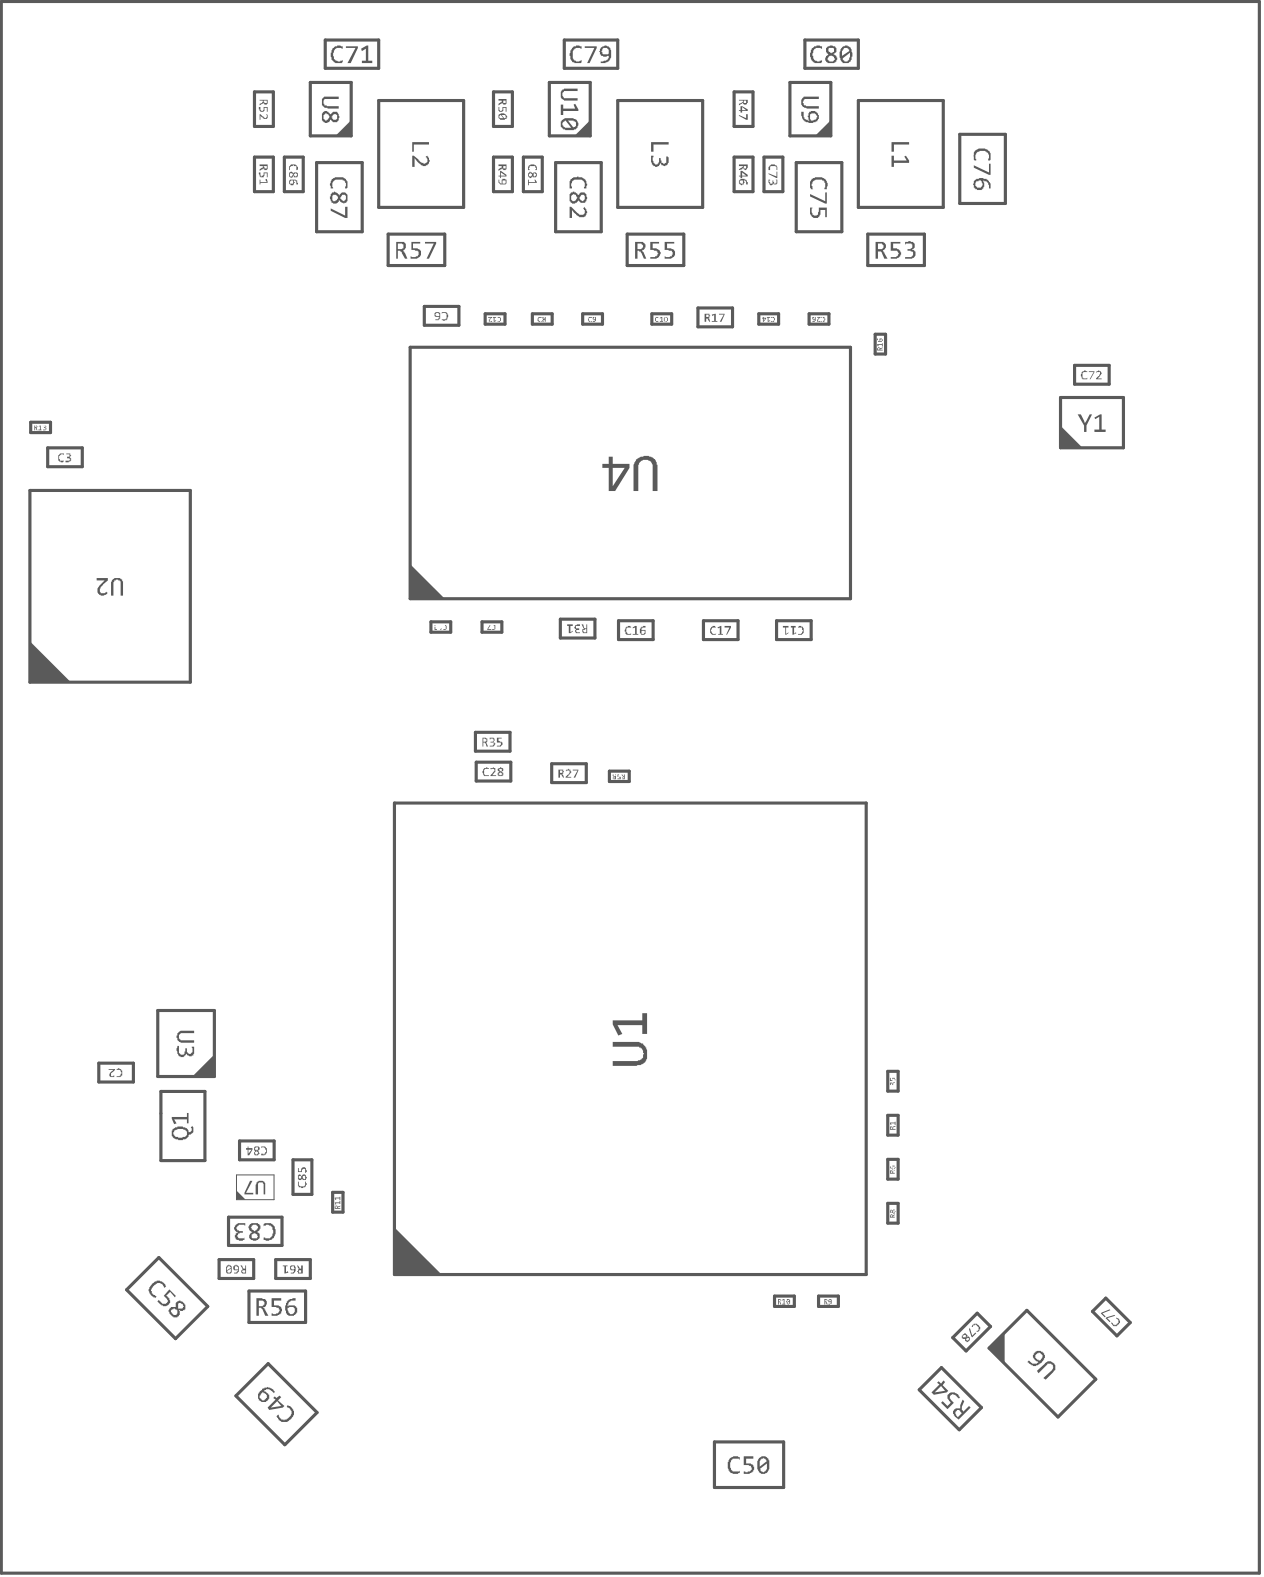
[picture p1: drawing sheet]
<svg xmlns="http://www.w3.org/2000/svg" width="134mm" height="167mm" viewBox="0 0 134 167" stroke-linecap="round" stroke-linejoin="round" font-family="sans-serif">
<path d="M.1 .2h133.1v166.3h-133.1z" fill="none" stroke="#5a5a5a" stroke-width=".33"/>
<g fill="#5a5a5a">
<path d="M25 126l1 .9h-1z"/>
<path d="M86.2 14.4l1.7-1.7v1.7z"/>
<path d="M60.8 14.4l1.6-1.7v1.7z"/>
<path d="M35.5 14.4l1.6-1.7v1.7z"/>
<path d="M43.4 59.7l3.6 3.7h-3.6z"/>
<path d="M41.7 129.9l5 5h-5z"/>
<path d="M104.6 142.6l1.7-1.6v3.3z"/>
<path d="M22.7 111.6v2.3h-2.4z"/>
<path d="M3.2 67.9l4.3 4.3h-4.3z"/>
<path d="M112.2 45.1l2.3 2.3h-2.3z"/>
</g>
<path d="M25 124.3h4v2.6h-4z" fill="none" stroke="#5a5a5a" stroke-width=".11"/>
<g fill="none" stroke="#5a5a5a" stroke-width=".33">
<path d="M26.9 9.7h2v3.7h-2zM26.9 16.6h2v3.7h-2zM30.1 16.6h2v3.7h-2zM32.8 8.7h4.3v5.7h-4.3zM33.5 17.2h4.8v7.3h-4.8zM34.4 4.2h5.7v3h-5.7zM40.1 10.6h8.9v11.3h-8.9zM52.2 9.7h2v3.7h-2zM52.2 16.6h2v3.7h-2zM55.4 16.6h2v3.7h-2zM58.1 8.7h4.3v5.7h-4.3zM58.8 17.2h4.8v7.3h-4.8z"/>
<path d="M59.7 4.2h5.6v3h-5.6zM65.3 10.6h9v11.3h-9zM77.7 9.7h1.9v3.7h-1.9zM77.7 16.6h1.9v3.7h-1.9zM80.8 16.6h2v3.7h-2zM83.6 8.7h4.3v5.7h-4.3zM84.2 17.2h4.8v7.3h-4.8zM85.1 4.2h5.7v3h-5.7zM90.8 10.6h9v11.3h-9zM101.5 14.2h4.8v7.3h-4.8zM41.1 24.8h5.9v3.3h-5.9zM43.4 36.7h46.6v26.7h-46.6z"/>
<path d="M44.9 32.4h3.6v2h-3.6zM51.3 33.2h2.1v1.1h-2.1zM56.3 33.2h2.1v1.1h-2.1zM61.6 33.2h2.1v1.1h-2.1zM66.3 24.8h6v3.3h-6zM69 33.2h2v1.1h-2zM73.8 32.6h3.7v2h-3.7zM80.3 33.2h2.1v1.1h-2.1zM85.6 33.2h2.1v1.1h-2.1zM91.8 24.8h6v3.3h-6zM92.6 35.4h1.1v2.1h-1.1zM113.7 38.7h3.6v2h-3.6z"/>
<path d="M3.2 51.9h16.9v20.3h-16.9zM3.2 44.7h2.1v1.1h-2.1zM5 47.4h3.7v2h-3.7zM112.2 42.1h6.6v5.3h-6.6zM45.6 65.8h2.1v1.1h-2.1zM50.3 77.5h3.6v2h-3.6zM51 65.8h2.1v1.1h-2.1zM59.3 65.5h3.6v2h-3.6zM65.4 65.7h3.7v2h-3.7zM74.4 65.7h3.7v2h-3.7zM82.1 65.7h3.7v2h-3.7zM41.7 85h49.9v49.9h-49.9z"/>
<path d="M50.4 80.6h3.6v2h-3.6zM58.4 80.8h3.6v2h-3.6zM64.5 81.6h2.1v1.1h-2.1zM10.5 112.5h3.6v2h-3.6zM16.7 106.9h6v7h-6zM17 115.5h4.7v7.3h-4.7zM93.9 113.4h1.1v2.1h-1.1zM93.9 118h1.1v2.1h-1.1zM13.4 136.5l3.4-3.4 5.2 5.1-3.4 3.4zM23.2 133.3h3.6v2h-3.6zM24.2 128.8h5.6v3h-5.6zM25.3 120.7h3.7v2h-3.7z"/>
<path d="M26.3 136.6h6v3.3h-6zM29.2 133.3h3.6v2h-3.6zM31 122.7h2v3.7h-2zM35.2 126.2h1.1v2.1h-1.1zM81.9 137.1h2.1v1.1h-2.1zM86.6 137.1h2.1v1.1h-2.1zM93.9 127.3h1.1v2.1h-1.1zM93.9 122.7h1.1v2.1h-1.1zM115.6 138.8l1.4-1.4 2.6 2.5-1.5 1.5zM25 147.7l3.4-3.4 5.1 5.2-3.4 3.4zM75.6 152.6h7.3v4.8h-7.3zM97.2 147.1l2.4-2.4 4.2 4.2-2.3 2.4z"/>
<path d="M100.8 141.5l2.6-2.6 1.4 1.5-2.6 2.5zM104.6 142.6l4-4 7.3 7.3-4 4z"/>
</g>
<g fill="#5a5a5a">
<path d="M27.1 125.1h.1a.48 .48 0 0 1 .7-.1l.2 .2v1.2h-.2v-1a.28 .28 0 0 0-.2-.3 .28 .28 0 0 0-.3 .1h-.1v1.2h-.3v-1z"/>
<path d="M26.4 124.9h.3l-.7 1.3h.8v.2h-.9v-.2z"/>
<path d="M43.5 25.6h.9v.2h-.7v.5h.5v.1a.32 .32 0 0 1 .3 .4v.1a.59 .59 0 0 1-.6 .5h-.5v-.3l.2 .1a.6 .6 0 0 0 .7-.2v-.4l-.1-.1-.7-.1z"/>
<path d="M45 25.6h1.1v.2l-.7 1.6h-.3l.8-1.6h-.9z"/>
<path d="M28.7 137.4h1v.2h-.7v.5h.5v.1l.2 .1a.63 .63 0 0 1-.5 .9h-.5v-.2h.1a.4 .4 0 0 0 .6-.1l.2-.2-.1-.3-.8-.1z"/>
<path d="M68.8 25.6h.9v.2h-.7v.5h.5v.1a.45 .45 0 0 1 .2 .7l-.2 .3h-.7v-.3v.1h.5l.3-.3-.1-.4-.7-.1z"/>
<path d="M70.3 25.6h1v.2h-.7v.5a.87 .87 0 0 1 .7 .1l.1 .2a.45 .45 0 0 1-.2 .6 .63 .63 0 0 1-.7 .2h-.2v-.3l.2 .1a.55 .55 0 0 0 .6-.2 .31 .31 0 0 0 0-.4 .31 .31 0 0 0-.4-.1v-.1h-.4z"/>
<path d="M100.2 147.6l.1-.1a.73 .73 0 0 1 1.1 .2l.2 .1-.2 .2-.3-.4h-.2a.3 .3 0 0 0-.3 0 .3 .3 0 0 0-.1 .3l.4 .5-.7 .7-.7-.7 .2-.1 .5 .5 .4-.4-.2-.2a.55 .55 0 0 1-.2-.6z"/>
<path d="M94.2 25.6h1v.2h-.7v.5h.4v.1a.3 .3 0 0 1 .3 .3h.1v.3h-.1a.3 .3 0 0 1-.3 .3v.1h-.7v-.2h.2a.46 .46 0 0 0 .6-.2 .26 .26 0 0 0 0-.4 .26 .26 0 0 0-.3-.1h-.5z"/>
<path d="M95.7 25.6h.4v-.1h.2l.1 .1a.32 .32 0 0 1 .4 .4v.2l-.3 .2a.32 .32 0 0 1 .3 .5 .32 .32 0 0 1-.3 .4v.1h-.8v-.2h.3a.38 .38 0 0 0 .5-.2 .24 .24 0 0 0 .1-.2 .24 .24 0 0 0-.3-.2v-.1h-.3v-.1h.2a.35 .35 0 0 0 .3-.5l-.1-.1h-.6l-.1 .1z"/>
<path d="M68.9 15h1.8v.3h-1.6v.8h-.2z"/>
<path d="M68.9 16.5h.2v.1h-.1a.55 .55 0 0 0 .2 .6 .22 .22 0 0 0 .2 .2 .22 .22 0 0 0 .2-.2h.1v-.5h.2v.3h.1v.2h.1a.3 .3 0 0 0 .3 0 .3 .3 0 0 0 .1-.4v-.2a.34 .34 0 0 1 .2 .5l-.1 .3-.1 .1a.33 .33 0 0 1-.5-.1l-.1-.2-.1 .1a.45 .45 0 0 1-.5 .4v-.1a.3 .3 0 0 1-.3-.4h-.1z"/>
<path d="M43.6 15h1.8v.3h-1.6v.8h-.2z"/>
<path d="M43.6 16.5h.2l.6 .7h.4v.1a.34 .34 0 0 0 .4-.4l-.1-.3h-.1l.2-.1 .2 .2v.2a.38 .38 0 0 1-.2 .5l-.2 .2-.5-.1-.6-.8v1h-.3z"/>
<path d="M94.3 15h1.9v.3h-1.6v.8h-.3z"/>
<path d="M94.3 16.5h.3v.5h1.3l-.2-.4 .1-.1 .4 .5v.2h-1.6v.5h-.3z"/>
<path d="M35.1 19a1.45 1.45 0 0 1 1.2-.2 .73 .73 0 0 1 .4 1.1h-.3a.55 .55 0 0 0 .2-.6h-.1v-.1a1.27 1.27 0 0 0-1.3 0v.1v.6h-.2l-.1-.5z"/>
<path d="M35 22.1l1.5 .7v-.9h.3v1.2h-.3l-1.5-.8z"/>
<path d="M27.9 129.5a.98 .98 0 0 1 1.1 .2 1.15 1.15 0 0 1-.2 1.4l-.1 .1h-.2v.1l-.6-.1v-.3l.2 .1a.46 .46 0 0 0 .6-.2h.1v-.3h.1l-.1-.5a.3 .3 0 0 0-.3-.3l-.1-.1h-.3v.1l-.2 .1z"/>
<path d="M24.8 129.7l.2-.1a.63 .63 0 0 1 .7-.2h.2v.3a.57 .57 0 0 0-.9 .3l.3 .3h.4v.1h-.3l-.3 .3a.35 .35 0 0 0 .5 .3h.3v-.1v.3l-.6 .1v-.1h-.3l-.1-.1-.1-.4 .4-.3a.43 .43 0 0 1-.4-.6z"/>
<path d="M60.3 19l.4-.2h.1a1.26 1.26 0 0 1 1.1 .2l.2 .6-.1 .1v.2h-.2a.56 .56 0 0 0 0-.7 .56 .56 0 0 0-.6-.2 .6 .6 0 0 0-.8 .5l.1 .4h-.3v-.7z"/>
<path d="M60.2 21.9h.2l.8 .7a.36 .36 0 0 0 .6 0 .4 .4 0 0 0-.1-.5l.2-.2v.2a.33 .33 0 0 1 .1 .5 .47 .47 0 0 1-.7 .4l-.3-.2-.5-.6v.9h-.3z"/>
<path d="M85.9 5.2l.2-.3h.3v-.1l.6 .1v.3l-.3-.1a.46 .46 0 0 0-.6 .2h-.1v.3l-.1 .1v.2l.1 .1a.32 .32 0 0 0 .4 .4v.1h.3v-.1l.3-.1v.3a.8 .8 0 0 1-1.2-.4l-.1-.6h.1z"/>
<path d="M60.5 5.1l.2-.2h.2v-.1h.4l.2 .1v.3a.6 .6 0 0 0-.6-.1 .6 .6 0 0 0-.3 .6 .47 .47 0 0 0 .3 .7v.1h.4l.2-.2v.3a.84 .84 0 0 1-1.2-.3l-.1-.6z"/>
<path d="M61.9 4.9h1.2v.2l-.7 1.6h-.3l.8-1.6h-1z"/>
<path d="M103.1 16a1.38 1.38 0 0 1 1.3-.2v.1a.79 .79 0 0 1 .3 1.1h-.2v-.2a.45 .45 0 0 0-.1-.7 .63 .63 0 0 0-.7-.1l-.1 .1a.46 .46 0 0 0-.4 .5l.1 .4h-.2l-.2-.5h.1z"/>
<path d="M103 17.5l1.6 .7v-.9h.2v1.2h-.2l-1.6-.8z"/>
<path d="M85.9 18.9a1.48 1.48 0 0 1 1.5 .1l.1 .3v.7h-.3v-.1h.1a.63 .63 0 0 0-.6-.9h-.1a.53 .53 0 0 0-.7 .3v.1v.3v.2l.1 .1h-.2l-.1-.4a.55 .55 0 0 1 .2-.6z"/>
<path d="M85.7 20.5l1.6 .8v-.9h.2v1.1h-.2l-1.6-.7z"/>
<path d="M85.7 22h.2v.1a.6 .6 0 0 0 .2 .7l.4-.1 .1-.7h.9v1h-.2v-.8h-.5v.5h-.1a.32 .32 0 0 1-.4 .4h-.1a.59 .59 0 0 1-.5-.6z"/>
<path d="M35.2 5.2l.2-.3h.3v-.1l.6 .1v.3l-.3-.1a.46 .46 0 0 0-.6 .2h-.1v.3h-.1l.1 .5a.3 .3 0 0 0 .4 .3v.1h.3v-.1l.3-.1v.3a.98 .98 0 0 1-1.1-.2 1.12 1.12 0 0 1 0-1.2z"/>
<path d="M36.6 4.9h1.3v.2l-.8 1.6h-.3l.8-1.6h-1z"/>
<path d="M38.2 5.2l.6-.4h.2v1.6h.4v.3h-1.1v-.3h.4v-1.2l-.4 .2z"/>
<path d="M16.1 135.8l.4-.2a.86 .86 0 0 1 1.1 .5l-.2 .2-.2-.5h-.3a1.04 1.04 0 0 0-.9 .8l.1 .1a.3 .3 0 0 0 .3 .3l.2 .2-.2 .2v-.1a.76 .76 0 0 1-.6-.6 .76 .76 0 0 1 .3-.8z"/>
<path d="M16.6 137.7l.2-.2 .2 .2a.39 .39 0 0 0 .4 .3 .39 .39 0 0 0 .3-.5l-.4-.4 .6-.7 .7 .7-.1 .2-.5-.6-.4 .4 .3 .3a.45 .45 0 0 1-.2 .7l-.5 .1v-.1h-.1z"/>
<path d="M77.2 154.3l.4-.2h.5v.1h.1v.2v-.1h-.3a.38 .38 0 0 0-.5 .2 .63 .63 0 0 0-.2 .7l.1 .2a.32 .32 0 0 0 .4 .3h.5v-.1v.3h-.2a.84 .84 0 0 1-1-.6v-.6h.1z"/>
<path d="M78.7 154.1h1v.2h-.8v.6h.4a.51 .51 0 0 1 .4 .7l-.1 .2-.3 .1h-.6v-.2h.1v.1h.3l.1-.1a.32 .32 0 0 0 .3-.4h-.1v-.2l-.2-.1h-.5z"/>
<path d="M29.2 149.9l.3-.2 .1 .3 .1 .2a.88 .88 0 0 0 1.1-.6v-.3l-.1-.3-.4-.1 .1-.2 .1 .1a.79 .79 0 0 1 .5 1.1l-.2 .2a.81 .81 0 0 1-1.2 .2h-.1z"/>
<path d="M29.9 133.9h.5v.1h-.1v.7l.1-.2 .1 .2h-.4v-.7h-.2z"/>
<path d="M27.4 11.3h.1v.3a.18 .18 0 0 0 .3 .1 .18 .18 0 0 0 .1-.2v-.2h.4v.5h-.1v-.4h-.2v.3a.26 .26 0 0 1-.3 .1 .26 .26 0 0 1-.2-.2h-.1z"/>
<path d="M27.5 12.1l.4 .2a.18 .18 0 0 0 .2 .2 .18 .18 0 0 0 .1-.2l-.1-.1 .1-.1a.28 .28 0 0 1 .1 .3 .28 .28 0 0 1-.2 .2h-.2l-.4-.3v.4z"/>
<path d="M27.4 18.2h.1v.4l.1 .1 .3-.2v-.3h.4v.6h-.1v-.5h-.2v.2a.25 .25 0 0 1-.3 .3 .25 .25 0 0 1-.2-.3z"/>
<path d="M27.5 19v.3h.7l-.1-.3 .1-.1 .1 .4h-.8v.2z"/>
<path d="M52.7 11.3h.1v.3a.18 .18 0 0 0 .2 .1 .18 .18 0 0 0 .2-.2v-.2h.4v.5h-.1v-.4h-.3a.29 .29 0 0 1-.2 .4 .29 .29 0 0 1-.3-.4z"/>
<path d="M78.2 12.2l.7 .3v-.4h.2v.6h-.2l-.7-.4z"/>
<path d="M51.8 78.1a.34 .34 0 0 1 .5 .2l-.2 .2 .3 .2-.1 .1a.38 .38 0 0 1-.5 .2v-.1h.3l.1-.1v-.2h-.3v-.1h.2a.18 .18 0 0 0 .1-.2 .18 .18 0 0 0-.2-.2l-.2 .1z"/>
<path d="M52.6 78.1h.5h-.4v.3l.3 .1a.22 .22 0 0 1 .2 .2 .22 .22 0 0 1-.2 .2v.1h-.4v-.1h.3l.1-.1v-.2h-.4z"/>
<path d="M60.8 66.1h.5v.1h-.4v.3h.4v.2h-.3l-.1 .1 .1 .1h.3v.1a.34 .34 0 0 1-.5-.3l.2-.1-.2-.1z"/>
<path d="M60 66.1h.6v.1h-.3v.7l.3-.2-.3 .3h-.1v-.8h-.2z"/>
<path d="M59.8 81.5l.3-.1h.2l.1 .4-.4 .4h.4v.1h-.6l.4-.5v-.3h-.2l-.1 .1z"/>
<path d="M60.6 81.4h.6l-.4 .9h-.1l.4-.8h-.5z"/>
<path d="M75.3 33.3l.4-.1v.8h.2h-.6h.2v-.7l-.1 .2z"/>
<path d="M76.1 33.2h.5l-.3 .8h-.2l.5-.7h-.5z"/>
<path d="M30.6 17.6a.54 .54 0 0 1 .5-.2 .54 .54 0 0 1 .4 .4l-.1 .2v-.4h-.3v-.1l-.3 .1a.24 .24 0 0 0-.1 .2 .24 .24 0 0 0 .1 .2h-.2z"/>
<path d="M31.5 125h.2h-.1a.34 .34 0 0 0 0 .4 .34 .34 0 0 0 .3 .1h.2a.38 .38 0 0 0 .2-.5l.1 .2v.3h-.1a.33 .33 0 0 1-.5 .1 .34 .34 0 0 1-.3-.5z"/>
<path d="M31.5 123.6h.1v.3h.3a.28 .28 0 0 1 .1-.4 .28 .28 0 0 1 .4 .3v.3h-.1v-.4h-.3l-.1 .1v.2h-.4z"/>
<path d="M27.6 121.3a.38 .38 0 0 1 .5 .2l.1 .1a.55 .55 0 0 1-.1 .6h-.1h-.4v-.1l.3 .1 .2-.3v-.4l-.1-.1h-.3l-.1 .1z"/>
<path d="M55.9 17.5l.5-.1a.42 .42 0 0 1 .4 .4v.2h-.2l.1-.1-.1-.3h-.6v.1h-.1l.1 .3h-.1z"/>
<path d="M55.9 19v.3h.7l-.1-.3h.1l.2 .3h-.9v.3z"/>
<path d="M102.8 140.3l.2-.2a.52 .52 0 0 1 .6 .2 .52 .52 0 0 1 0 .5l-.1 .1-.2-.1a.31 .31 0 0 0 .2-.3 .31 .31 0 0 0-.2-.3h-.2h-.2v.2z"/>
<path d="M102.6 140.5l.2 .8 .4-.3 .1 .1-.5 .4-.3-.8z"/>
<path d="M117.5 140l.1-.1 .1 .3h.2h.2v-.1a.32 .32 0 0 0 .2-.4 .32 .32 0 0 0-.3-.2l.1-.1v.1h.2l.1 .1a.3 .3 0 0 1 .1 .4 .3 .3 0 0 1-.3 .2 .32 .32 0 0 1-.3 .1 .32 .32 0 0 1-.3-.2z"/>
<path d="M117 139.5l.9-.4 .1 .1-.9 .3 .4 .3-.1 .1z"/>
<path d="M116.4 139l1-.5 .1 .1-.9 .4 .4 .3-.1 .1z"/>
<path d="M81.3 17.7h.1a.44 .44 0 0 1 .5-.3 .44 .44 0 0 1 .3 .5v.1h-.1a.24 .24 0 0 0 0-.3 .24 .24 0 0 0-.2-.1h-.4v.1v.1h-.1h.1v.2h-.2z"/>
<path d="M81.3 18.3l.8 .4v-.5h.1v.6l-.9-.4z"/>
<path d="M81.3 19h.2l-.1 .1 .1 .3h.2v-.3l.2 .2v.1h.2v-.1v-.2v-.1h.1a.34 .34 0 0 1-.2 .5l-.2-.2a.22 .22 0 0 1-.2 .3 .22 .22 0 0 1-.2-.3h-.1z"/>
<path d="M51.1 81.4l.4-.2 .2 .1v.1a.34 .34 0 0 0-.5 .2v.3a.38 .38 0 0 0 .5 .1l-.1 .1a.34 .34 0 0 1-.5-.2l-.1-.1z"/>
<path d="M51.9 81.3h.2v-.1l.3 .1a.38 .38 0 0 1-.2 .5l-.1 .2h.4v.1h-.6l.2-.4 .2-.1-.1-.2h-.2z"/>
<path d="M75.1 66.5l.1-.1a.33 .33 0 0 1 .5-.1v.1a.34 .34 0 0 0-.3 0 .34 .34 0 0 0-.2 .3l.1 .2a.24 .24 0 0 0 .2 .2 .24 .24 0 0 0 .2-.1v.2a.38 .38 0 0 1-.5-.2h-.1z"/>
<path d="M75.9 66.4l.4-.2v.9h.2v.1h-.5v-.1h.1v-.7l-.1 .1z"/>
<path d="M76.6 66.2h.7v.2l-.4 .8h-.1l.4-.8h-.6z"/>
<path d="M66.2 66.4l.1-.1a.24 .24 0 0 1 .3-.1 .24 .24 0 0 1 .2 .2 .34 .34 0 0 0-.6 .3 .3 .3 0 0 0 .2 .3 .3 .3 0 0 0 .4 0v.2h-.1a.34 .34 0 0 1-.5-.3l-.1-.1z"/>
<path d="M66.9 66.4l.3-.2h.1v.9h.2v.1h-.6v-.1h.3v-.7l-.3 .1z"/>
<path d="M84.4 66.3l.2-.1a.42 .42 0 0 1 .4 .5v.1a.32 .32 0 0 1-.4 .4h-.2v-.2a.24 .24 0 0 0 .3 .1 .24 .24 0 0 0 .1-.3h.1l-.1-.4h-.4z"/>
<path d="M83.7 66.2h.5v.2h-.2v.7l.2-.2v.1l-.4 .2v-.8h-.1z"/>
<path d="M82.8 66.2h.6v.2h-.3v.7l.3-.2v.1l-.3 .2v-.8h-.3z"/>
<path d="M46.7 33h.1a.34 .34 0 0 1 .5 .3h.1v.2l-.2 .4-.3 .1-.2-.2a.34 .34 0 0 0 .5-.3v-.2a.3 .3 0 0 0-.5-.1z"/>
<path d="M6.2 48.2h.1a.38 .38 0 0 1 .5-.2v.2l-.2-.1a.32 .32 0 0 0-.3 .4v.2h.5a.24 .24 0 0 1-.2 .2 .24 .24 0 0 1-.3-.1 .43 .43 0 0 1-.1-.6z"/>
<path d="M7 48h.4l.1 .2-.1 .2a.22 .22 0 0 1 .1 .3 .22 .22 0 0 1-.2 .1v.1h-.4v-.2a.38 .38 0 0 0 .5-.1v-.1h-.3v-.2h.3v-.2h-.4z"/>
<path d="M12.3 113.1h.1a.39 .39 0 0 1 .4 .1 .39 .39 0 0 1 .1 .4 .32 .32 0 0 1-.4 .4h-.2v-.2a.24 .24 0 0 0 .3 .1 .24 .24 0 0 0 .2-.3 .37 .37 0 0 0-.1-.3 .37 .37 0 0 0-.4-.1z"/>
<path d="M11.5 113.1h.7l-.3 .4a.24 .24 0 0 0-.2 .1 .24 .24 0 0 0 .1 .3l.3-.1v.2a.34 .34 0 0 1-.5-.3l.1-.2 .3-.3h-.5z"/>
<path d="M65.3 81.9h.4l-.3 .1v.2h.3v.3h-.4v-.1h.3l-.1-.2h-.2z"/>
<path d="M92.8 36.4h.5l.1-.1v.4h-.1v-.2h-.4l.1 .1-.1 .1z"/>
<path d="M4.1 45.1l.2-.1v.5h.1h-.3h.1v-.4z"/>
<path d="M4.6 45v.1v-.1h.2l.1 .1-.1 .1 .1 .3h-.1h-.2h.2v-.2h-.2l.2-.2z"/>
<path d="M35.4 127.2h.5v-.1h.1v.3l-.1-.1h-.4l.1 .1-.1 .1z"/>
<path d="M35.4 126.7h.5l.1-.1v.4h-.1v-.2h-.4l.1 .2h-.1z"/>
<path d="M82.7 137.5l.3-.1v.6h.1h-.4h.2v-.5l-.2 .1z"/>
<path d="M94.1 114h.1v.3h.2v-.3h.2l.1 .3-.1 .1v-.2l-.1-.1-.1 .3h-.3z"/>
<path d="M94.1 118.8h.5l.1-.1v.3h-.1v-.1h-.4l.1 .1h-.1z"/>
<path d="M86.9 33.5h.3v.2h.1l-.1 .3h-.3a.21 .21 0 0 0 .3-.1 .21 .21 0 0 0 0-.2 .21 .21 0 0 0-.3-.1z"/>
<path d="M86.4 33.5h.4l-.3 .3 .1 .2h.2a.19 .19 0 0 1-.3 0 .19 .19 0 0 1-.1-.2l.3-.2h-.3z"/>
<path d="M81.5 33.5h.2a.24 .24 0 0 1 .3 .2 .24 .24 0 0 1-.1 .3h-.4a.19 .19 0 0 0 .3-.1 .19 .19 0 0 0-.1-.3v-.1l-.1 .1z"/>
<path d="M81.1 33.5h.4v.1h-.2v.4l.2-.1v.1h-.3v-.4z"/>
<path d="M46.9 66.1v.1a.21 .21 0 0 1 .3 0 .21 .21 0 0 1 0 .3v.2h-.3v-.1a.19 .19 0 0 0 .3-.1 .19 .19 0 0 0-.1-.3v-.1z"/>
<path d="M46.4 66.1h.3h-.1v.5l.1-.1v.1l-.1 .1v-.6z"/>
<path d="M46 66.1h.3h-.2l-.1 .1 .1 .2h.1h-.1v.2h.1v.1h-.2v-.3h.1h-.1z"/>
<path d="M52.6 33.5h.2a.27 .27 0 0 1 .2 .4 .27 .27 0 0 1-.4 .1h.1h.2v-.4h-.2v-.1l-.1 .1z"/>
<path d="M52.1 33.5h.4v.1h-.2v.4l.2-.1v.1h-.3v-.4z"/>
<path d="M51.6 33.5h.5l-.3 .3v.2h.3a.19 .19 0 0 1-.3 0 .19 .19 0 0 1-.1-.2l.3-.2h-.4z"/>
<path d="M69.3 33.6l.1-.1h.2v.1l-.1-.1v.1h-.1v.4h.1h.1h-.2h-.1z"/>
<path d="M69.8 33.6l.3-.1v.5h-.3h.2v-.4l-.2 .1z"/>
<path d="M62.3 33.5h.3v.1h-.2v-.1l-.1 .2v.2l.1 .1h.2a.24 .24 0 0 1-.3 0 .24 .24 0 0 1-.1-.2z"/>
<path d="M57 33.5h.3v.1h-.2v-.1l-.1 .2v.2l.1 .1h.2a.24 .24 0 0 1-.3 0 .24 .24 0 0 1-.1-.2z"/>
<path d="M52.1 66.1v.1a.21 .21 0 0 1 .3 0 .21 .21 0 0 1 0 .3l-.1 .2h-.2v-.1a.19 .19 0 0 0 .2-.1 .19 .19 0 0 0-.1-.3v-.1z"/>
<path d="M51.8 66.1h.1l-.3 .5h.4v.1h-.5z"/>
<path d="M84.9 10.3l.1-.1h1.6v.3h-1.5l-.1 .2h-.1l.1 .4 .3 .1h1.3v.3h-1.3l-.2-.1a.73 .73 0 0 1-.2-1.1z"/>
<path d="M59.4 9.5h.3v-.1h1.4v.2h-1.2a.38 .38 0 0 0-.4 .4 .38 .38 0 0 0 .4 .4h1.2v.2h-1.2a.63 .63 0 0 1-.6-.3 .63 .63 0 0 1 .1-.7z"/>
<path d="M59.3 11.1h.3v.4h1.2l-.1-.4 .1-.1 .4 .6v.1h-1.6v.5h-.3z"/>
<path d="M34.1 10.5l.2-.3h1.5v.3h-1.3a.28 .28 0 0 0-.3 .2 .28 .28 0 0 0 .1 .3v.2h.3h1.2v.3h-1.2v-.1a.54 .54 0 0 1-.5-.2 .54 .54 0 0 1 0-.6z"/>
<path d="M67.3 48.7a1.53 1.53 0 0 1 2-.1l.2 .3v.3v2.8h-.5v-2.6a.76 .76 0 0 0-.3-.7 .76 .76 0 0 0-.8 0l-.3 .3v.2h-.1v2.8h-.5v-2.4a.87 .87 0 0 1 .2-.8z"/>
<path d="M64.8 110.2h2.5a1.15 1.15 0 0 1 1.1 .9 1.65 1.65 0 0 1-.3 1.4l-.8 .3h-2.5v-.5h2.6l.3-.1 .3-.3v-.3l.1-.1-.1-.2a.43 .43 0 0 0-.4-.5h-2.8z"/>
<path d="M64.8 108h3.1v-.8h.5v2.2h-.5v-.9h-2.6l.5 .9-.4 .2-.6-1.2z"/>
<path d="M109.7 145.1l.9-.9a.56 .56 0 0 1 .9 .2l.1 .1a.38 .38 0 0 1-.1 .6l-.9 .9-.2-.2 1-.9 .1-.3h-.1v-.1a.55 .55 0 0 0-.6-.2l-.9 1z"/>
<path d="M18.2 118.2h1.6v-.4h.1v1.1h-.1v-.5h-1.4l.3 .5h-.3z"/>
<path d="M18.8 109.3l.3-.2h1.4v.2h-1.2a.32 .32 0 0 0-.4 .4 .32 .32 0 0 0 .5 .4h1.1v.2h-1.4v-.1a.32 .32 0 0 1-.3-.4h-.1z"/>
<path d="M18.8 110.7h.1v.3a.38 .38 0 0 0 .2 .5 .24 .24 0 0 0 .3 .1 .24 .24 0 0 0 .1-.3h.1v-.4h.2v.3a.32 .32 0 0 0 .4 .3v-.1a.36 .36 0 0 0 .1-.6h.2v.4a.44 .44 0 0 1-.2 .5 .44 .44 0 0 1-.5-.1l-.1-.2v.2h-.1a.39 .39 0 0 1-.4 .3 .39 .39 0 0 1-.4-.4v-.2l-.1-.1z"/>
<path d="M11.9 61.3a.72 .72 0 0 1 .9-.1l.2 .3v1.5h-.2v-1.5l-.3-.1v-.1h-.2l-.3 .3v1.4h-.3v-1.4z"/>
<path d="M10.2 61.2h1.2v.2l-.8 .9a.34 .34 0 0 0 0 .3 .34 .34 0 0 0 .3 .2l.3-.1v-.1l.2 .2h-.1a.57 .57 0 0 1-.8 .1 .57 .57 0 0 1-.1-.8l.7-.7h-.9z"/>
<path d="M114.4 39.4l.3-.1v-.1h.1l.2 .2a.34 .34 0 0 0-.5 .2v.3a.3 .3 0 0 0 .5 .1v.1h-.1a.34 .34 0 0 1-.5-.2l-.1-.1z"/>
<path d="M115.2 39.3h.6l-.5 .8 .4-.7h-.5z"/>
<path d="M115.9 39.4l.2-.1a.25 .25 0 0 1 .3 0 .25 .25 0 0 1 0 .3l-.3 .4h.4v.1h-.6l.4-.3v-.2h.1a.19 .19 0 0 0-.1-.2 .19 .19 0 0 0-.3 .1z"/>
<path d="M114 43.8h.3l.5 1 .5-1h.2l-.6 1.2v.7h-.2v-.7z"/>
<path d="M115.8 44.2l.6-.4h.1v1.7h.5v.2h-1.2v-.2h.5v-1.4l-.4 .3z"/>
<path d="M42.1 25.8v.6h.3a.28 .28 0 0 0 .3-.2 .28 .28 0 0 0-.1-.3l-.1-.1zM41.9 25.6h.7a.32 .32 0 0 1 .3 .4v.1a.44 .44 0 0 1-.3 .4l.2 .1 .3 .8h-.3l-.5-.9h-.2v.9h-.2z"/>
<path d="M27.4 137.6v.6h.2a.32 .32 0 0 0 .4-.4l-.2-.2zM27.1 137.4h.6h.2a.35 .35 0 0 1 .3 .6l-.1 .2-.3 .2h.2v.1h.1l.3 .7h-.3l-.3-.7-.2-.1h-.2v.8h-.3z"/>
<path d="M30.4 138.4v.2l.1 .1a.32 .32 0 0 0 .4 .4 .42 .42 0 0 0 .3-.6 .42 .42 0 0 0-.6-.2v.1zM30.3 137.7l.4-.3h.2h.4v.2a.67 .67 0 0 0-.8 .3l-.1 .3 .3-.1a.58 .58 0 0 1 .6 .1 .58 .58 0 0 1 .1 .7l-.1 .2a.87 .87 0 0 1-.8 .1l-.1-.1a1.15 1.15 0 0 1-.1-1.1z"/>
<path d="M67.4 25.8v.6h.3a.32 .32 0 0 0 .3-.5l-.1-.1zM67.2 25.6h.7a.46 .46 0 0 1 .4 .6h-.1l-.1 .2-.2 .1 .2 .2 .3 .7h-.3l-.3-.8h-.2v-.1h-.2v.9h-.2z"/>
<path d="M101.1 149.4v.2l.2 .4 .4-.5-.1-.1a.22 .22 0 0 0-.2-.2 .22 .22 0 0 0-.3 .2zM101.8 148.1l.2 .2-.3 .6v.3l.1 .1 .1 .1 .6-.6 .2 .1-1.3 1.3-.5-.4-.1-.4a.46 .46 0 0 1 .6-.4h.2v.1v-.4z"/>
<path d="M98.9 147.3l1.1-.1-.5-.5zM99.1 146.3l.2-.1 .2 .2 .3-.3 .2 .1-.3 .4 .6 .6-.2 .1-1.3 .3-.3-.3 .9-.8z"/>
<path d="M92.9 25.8v.6h.3a.26 .26 0 0 0 .3-.3 .26 .26 0 0 0-.2-.2v-.1zM92.6 25.6h.7a.46 .46 0 0 1 .4 .6l-.2 .2-.2 .1 .2 .2 .4 .7h-.4l-.3-.8h-.3v.8h-.3z"/>
<path d="M36.2 20.6l-.1 .3h-.1v.1l.3 .3 .1-.1a.38 .38 0 0 0 .2-.5l-.1-.1zM35.2 20.7v.1a.34 .34 0 0 0 .2 .5 .45 .45 0 0 0 .3-.5 .3 .3 0 0 0-.5-.1zM35 20.5l.4-.2 .3 .1 .2 .3a.44 .44 0 0 1 .6-.3 .44 .44 0 0 1 .3 .6v.3l-.2 .2h-.2l-.4-.1-.2-.2a.35 .35 0 0 1-.5 .3h-.2v-.2h-.1l-.1-.3z"/>
<path d="M26.6 130.6a.3 .3 0 0 0 .1 .4 .3 .3 0 0 0 .3 0h.2v-.1h.1l-.1-.1a.3 .3 0 0 0-.4-.3zM26.6 129.7v.1h-.1l.1 .1a.34 .34 0 0 0 .5 .3v-.1a.22 .22 0 0 0 .2-.2 .22 .22 0 0 0-.2-.2v-.1zM26.4 129.6a.63 .63 0 0 1 .7-.2 .46 .46 0 0 1 .4 .6l-.1 .3-.3 .1h.2a.43 .43 0 0 1 .2 .6h-.1a.59 .59 0 0 1-1-.1v-.4l.3-.1-.3-.1v-.1a.33 .33 0 0 1 0-.5z"/>
<path d="M61.3 20.8v.2v.1l.3 .2 .1-.1a.38 .38 0 0 0 .2-.5l-.1-.1h-.3zM60.4 20.7a.43 .43 0 0 0 .4 .6l.1-.1 .2-.3-.3-.4zM60.2 20.5l.2-.1h.2v-.1h.2v.1a.44 .44 0 0 1 .4 .3 .45 .45 0 0 1 .4-.3 .45 .45 0 0 1 .4 .2v.1a.4 .4 0 0 1-.1 .6v.1a.48 .48 0 0 1-.7-.3l-.1 .2a.44 .44 0 0 1-.5 .2 .44 .44 0 0 1-.4-.4z"/>
<path d="M87.6 5.2v.2l.2 .2a.3 .3 0 0 0 .3-.1 .3 .3 0 0 0 .1-.3l-.1-.1h-.4zM87.6 6l-.1 .2a.32 .32 0 0 0 .5 .3 .3 .3 0 0 0 .3-.3h-.1a.34 .34 0 0 0-.5-.3zM87.4 5.1h.1a.59 .59 0 0 1 1 .1 .34 .34 0 0 1-.3 .5h-.1l.4 .2a.52 .52 0 0 1-.1 .6 .52 .52 0 0 1-.5 .2h-.2a.46 .46 0 0 1-.4-.6h.1v-.2l.3-.2a.47 .47 0 0 1-.3-.6z"/>
<path d="M89.1 5.2v.2v.5l.7-.5a.32 .32 0 0 0-.4-.3zM89.1 6.2a.32 .32 0 0 0 .5 .3l.2-.2 .1-.7zM89 5.1l.1-.2a.63 .63 0 0 1 1 .6l.1 .1-.1 .7a.67 .67 0 0 1-1 .3 1.44 1.44 0 0 1-.1-1.5z"/>
<path d="M63.7 5.2v.1a.3 .3 0 0 0 .1 .4 .3 .3 0 0 0 .3 0 .28 .28 0 0 0 .3-.1 .28 .28 0 0 0-.1-.4 .38 .38 0 0 0-.5-.1zM63.5 5.2l.2-.2a.45 .45 0 0 1 .8 .1 .63 .63 0 0 1 .1 .6v.3a.93 .93 0 0 1-1.1 .7v-.2l.5-.1a.46 .46 0 0 0 .4-.6 .55 .55 0 0 1-.6 .2v-.1h-.2l-.1-.2v-.2h-.1l.1-.1z"/>
<path d="M103.3 19.2v.1a.3 .3 0 0 0 0 .5v.1a.46 .46 0 0 0 .6-.3v-.3a.24 .24 0 0 0-.2-.2 .24 .24 0 0 0-.3 .1zM103 19.2l.3-.3h.2l.1-.1h.4v.1a.73 .73 0 0 1 .8 .9v.1h-.2v-.3l-.1-.1a.32 .32 0 0 0-.4-.3l-.1-.1 .1 .2v.5h-.1a.32 .32 0 0 1-.4 .3h-.3v-.1a.32 .32 0 0 1-.3-.4l-.1-.1 .1-.1z"/>
<path d="M18.8 138v.5h.1a.3 .3 0 0 0 .5-.1 .3 .3 0 0 0-.1-.4l-.2-.1zM18.1 138.6v.2l.2 .2a.28 .28 0 0 0 .3 .1 .28 .28 0 0 0 .2-.4l-.3-.2h-.2zM17.9 138.5h.1a.44 .44 0 0 1 .6-.2 .47 .47 0 0 1 0-.5 .47 .47 0 0 1 .5-.2l.1 .1a.58 .58 0 0 1 .4 .6v.2l-.1 .1h-.1v.1l-.5-.1 .1 .1a.45 .45 0 0 1-.2 .6v.1a.6 .6 0 0 1-.7-.3l-.2-.1v-.2h-.1z"/>
<path d="M80.4 154.4v.2v.6l.7-.6-.3-.3zM80.4 155.4a.34 .34 0 0 0 .6 .3v-.1a.63 .63 0 0 0 .1-.7zM80.3 154.3h.1a.52 .52 0 0 1 .5-.2 .52 .52 0 0 1 .4 .4l.1 .1a1.64 1.64 0 0 1-.3 1.3h-.1a.63 .63 0 0 1-.9-.6v-.7z"/>
<path d="M28.6 148.9l1.1-.1-.4-.5zM28.9 147.9l.2-.1 .1 .1 .4-.2 .1 .1-.3 .4 .7 .6-.2 .1-1.4 .3-.2-.3 .9-.8z"/>
<path d="M27.6 147.4v.1a.33 .33 0 0 0-.1 .5h.1a.22 .22 0 0 0 .2 .2 .22 .22 0 0 0 .3-.2 .31 .31 0 0 0 .1-.4 .31 .31 0 0 0-.3-.2v-.1zM27.4 147.3l.2-.1a.77 .77 0 0 1 1.2-.2l.3 .2-.1 .2-.5-.4h-.4v.1l-.2 .1h.2v.1a.45 .45 0 0 1 .4 .5v.1a.6 .6 0 0 1-1 .3l-.2-.2v-.5z"/>
<path d="M31.6 134.4v.3h.3v-.3zM31.4 133.9h.1l.2 .3h.2v-.3h.1v.8h-.5l-.1-.2h.1v-.2h.2h-.1z"/>
<path d="M30.8 134v.2a.22 .22 0 0 0 .2 .1 .22 .22 0 0 0 .2-.1h-.1v-.2zM30.7 134l.1-.1a.34 .34 0 0 1 .3 0 .34 .34 0 0 1 .2 .3v.1a.34 .34 0 0 1-.5 .4h.2l.1-.3h.1a.34 .34 0 0 1-.5-.2z"/>
<path d="M25.6 134.5l.1 .2h.2v-.3h-.2zM25.4 133.9h.2l.2 .3h.1v-.3h.1v.8h-.3a.22 .22 0 0 1-.2-.2 .22 .22 0 0 1 .2-.2z"/>
<path d="M24.8 134v.2a.19 .19 0 0 0 .3 .1 .19 .19 0 0 0 .1-.2l-.1-.1zM24.7 134a.37 .37 0 0 1 .5-.1 .37 .37 0 0 1 .1 .5 .32 .32 0 0 1-.5 .3h.2l.2-.3a.34 .34 0 0 1-.5-.2z"/>
<path d="M24 134.5a.22 .22 0 0 0 .3 .2 .22 .22 0 0 0 .1-.3v-.2zM24.1 134l-.1 .4 .4-.2-.1-.2zM24 133.9h.2v-.1l.1 .1a.43 .43 0 0 1 .2 .6v.1a.38 .38 0 0 1-.5 .1h-.1v-.6z"/>
<path d="M27.9 10.6l.1 .3h.2v-.3zM27.5 10.6h.8v.3a.22 .22 0 0 1-.2 .2 .22 .22 0 0 1-.2-.2l-.4 .3v-.2l.3-.2v-.2h-.3z"/>
<path d="M27.9 17.6l.1 .2h.2v-.2zM27.5 17.4h.8v.4a.22 .22 0 0 1-.2 .2 .22 .22 0 0 1-.2-.3l-.1 .2-.3 .2v-.2l.3-.2v-.1h-.3z"/>
<path d="M53.2 10.6v.3h.3v-.3zM52.7 10.5h.9v.4a.22 .22 0 0 1-.2 .2 .22 .22 0 0 1-.2-.2l-.5 .3v-.2l.4-.2v-.2h-.4z"/>
<path d="M53.1 12.2l.3 .3a.21 .21 0 0 0 .1-.3 .21 .21 0 0 0-.3 0zM52.8 12.3l.1 .2h.3v.1v-.1l-.2-.3zM52.7 12.2a.52 .52 0 0 1 .6-.2 .52 .52 0 0 1 .4 .4h-.1v.2l-.3 .1a.38 .38 0 0 1-.5-.2h-.1z"/>
<path d="M53.2 17.6v.2h.3v-.2zM52.7 17.4h.9v.4a.22 .22 0 0 1-.3 .2 .22 .22 0 0 1-.1-.3l-.1 .2-.4 .2v-.2l.4-.2v-.1h-.4z"/>
<path d="M53 18.2v.4h.5zM52.9 18.1l.7 .4v.2h-.6v.1h-.1v-.1h-.2v-.1h.2z"/>
<path d="M53.2 19.1v.2a.21 .21 0 0 0 .3 .1 .21 .21 0 0 0 0-.3zM52.7 19h.1v.3l.3 .1a.34 .34 0 0 1 .2-.5 .28 .28 0 0 1 .3 .2 .28 .28 0 0 1-.1 .3v.1h-.2a.38 .38 0 0 1-.5-.2h-.1z"/>
<path d="M78.7 10.6v.3h.2v-.3zM78.2 10.6h.9v.3h-.1a.22 .22 0 0 1-.2 .2 .22 .22 0 0 1-.2-.2l-.4 .3v-.2l.4-.2v-.2h-.4z"/>
<path d="M78.5 11.3v.4h.4zM78.3 11.2h.2l.6 .4v.1h-.6v.2h-.2v-.2h-.1h.1z"/>
<path d="M78.7 17.6v.2h.2v-.2zM78.2 17.4h.9v.3l-.1 .1a.17 .17 0 0 1-.2 .2 .17 .17 0 0 1-.1-.2l-.1-.1-.1 .2-.3 .1v-.1l.4-.2v-.1h-.4z"/>
<path d="M78.5 18.2v.4h.4zM78.3 18.1h.2l.6 .4v.2h-.6v.1h-.2v-.1h-.1v-.1h.1z"/>
<path d="M78.2 19.2l.1 .2a.19 .19 0 0 0 .3-.1 .19 .19 0 0 0-.1-.2zM78.2 19l.1-.1h.5l.3 .4v.2h-.2v-.3l-.2-.1 .1 .2-.1 .2h-.2v.1l-.2-.1a.3 .3 0 0 1-.1-.5z"/>
<path d="M51.1 78.1v.4h.3l.1-.1v-.2zM51 78.1h.3a.26 .26 0 0 1 .2 .2 .26 .26 0 0 1-.1 .3h.1l.1 .4h-.1l-.2-.4h-.2v.4h-.1z"/>
<path d="M61.7 66.7l.1 .2h.2v-.3zM61.5 66.1h.2l.2 .4h.1v-.4h.1v.9h-.3a.24 .24 0 0 1-.2-.2 .24 .24 0 0 1 .1-.2l.1-.1h-.1z"/>
<path d="M59.2 81.5v.3h.3v-.3zM59.1 81.4h.5l.1 .3h-.1v.2h-.2h.1l.2 .4h-.1l-.2-.4h-.2v.4h-.1z"/>
<path d="M74.7 33.3v.2h.3v-.2zM74.5 33.2h.5l.1 .3h-.1v.1h-.1l.1 .1 .1 .3h-.1l-.1-.3h-.2v.3h-.2z"/>
<path d="M31.1 18.4v.1a.18 .18 0 0 0 .2 .2 .18 .18 0 0 0 .1-.3v-.1zM30.7 18.3v.4h.2l.1-.3-.1-.1zM30.6 18.2h.2h.2v.2a.28 .28 0 0 1 .4-.1 .28 .28 0 0 1 .1 .4l-.1 .1h-.3v-.2h-.1v.2h-.2a.34 .34 0 0 1-.2-.5z"/>
<path d="M30.7 19.2a.19 .19 0 0 0 .1 .2 .19 .19 0 0 0 .2-.1v-.2h-.2zM30.6 19.1l.2-.1a.55 .55 0 0 1 .6 .2l.1 .3h-.1v-.3l-.1-.1h-.2v.2h.1l-.1 .1a.24 .24 0 0 1-.2 .2 .24 .24 0 0 1-.2-.1l-.1-.1z"/>
<path d="M31.6 124.6a.15 .15 0 0 0 .3 0 .15 .15 0 0 0-.3 0zM32 124.4v.3l.3 .1v-.4h-.1zM31.5 124.4l.3-.1 .1 .1a.22 .22 0 0 1 .3-.1 .22 .22 0 0 1 .2 .2v.3a.24 .24 0 0 1-.3 .1 .24 .24 0 0 1-.2-.2 .23 .23 0 0 1-.3 .1 .23 .23 0 0 1-.1-.3z"/>
<path d="M27 121.9v.1a.18 .18 0 0 0 .2 .2 .18 .18 0 0 0 .1-.3l-.1-.1zM27 121.4v.3h.2h.1v-.3zM26.9 121.4l.1-.1a.34 .34 0 0 1 .5 .3l-.2 .1 .1 .3h.1l-.1 .1a.27 .27 0 0 1-.4 .1 .27 .27 0 0 1-.1-.3l.1-.1-.1-.1z"/>
<path d="M26.3 121.7v.4l.3-.4zM26 121.5h.2v-.2h.1v.2h.4v.2l-.3 .5h-.2v-.5h-.2z"/>
<path d="M56.4 18.3v.2l.1 .2a.18 .18 0 0 0 .2-.2 .18 .18 0 0 0-.3-.2zM55.9 18.4v.2l.2 .1a.18 .18 0 0 0 .2-.2 .18 .18 0 0 0-.3-.2zM55.9 18.3l.2-.1 .3 .2a.22 .22 0 0 1 .2-.2 .22 .22 0 0 1 .2 .3v.1a.24 .24 0 0 1-.2 .2 .24 .24 0 0 1-.2-.1v-.1l-.1 .1a.17 .17 0 0 1-.2 .1 .17 .17 0 0 1-.2-.1z"/>
<path d="M102.2 141.7a.18 .18 0 0 0 .2 .1 .18 .18 0 0 0 .1-.2h-.3zM101.9 141.3l-.1 .1a.19 .19 0 0 0 .3 .1 .19 .19 0 0 0 .1-.2zM101.7 141.3l.3-.2a.3 .3 0 0 1 .3 .3l-.1 .1 .2-.1a.31 .31 0 0 1 .2 .4 .31 .31 0 0 1-.4 .2l-.1-.2v-.1h-.3l-.1-.1z"/>
<path d="M52.8 81.4l.1 .2h.2l.1-.2h-.1zM52.7 81.9a.22 .22 0 0 0 .2 .1 .22 .22 0 0 0 .3-.1l-.3-.2zM52.6 81.4l.2-.1a.3 .3 0 0 1 .4 .2l-.1 .2a.23 .23 0 0 1 .1 .3 .23 .23 0 0 1-.3 .1h-.1a.22 .22 0 0 1-.2-.2 .22 .22 0 0 1 .2-.2l-.2-.2z"/>
<path d="M67.9 66.7v.4h.2l.1-.1v-.3zM67.9 66.3l.4-.1v.2h-.4v.1v.2h.4a.34 .34 0 0 1-.3 .5h-.1a.61 .61 0 0 1 0-.9z"/>
<path d="M46.1 33.2v.1a.24 .24 0 0 0 .1 .2 .24 .24 0 0 0 .3-.1v-.1a.24 .24 0 0 0-.2-.2 .24 .24 0 0 0-.2 .1zM46.1 33a.34 .34 0 0 1 .5 .3 .38 .38 0 0 1-.2 .5v.1h-.3v-.1h.2l.2-.3a.34 .34 0 0 1-.5-.2z"/>
<path d="M65.8 82.3v.1h.2v-.2zM65.7 81.9l.2 .2 .2-.2v.6h-.3v-.3l.1-.1z"/>
<path d="M65 82.2l-.1 .2h.2zM64.9 81.9l.1 .3 .2-.1-.1-.2zM64.8 81.9h.4v.1l-.1 .2h.1v.3h-.3l-.1-.1 .1-.1z"/>
<path d="M92.9 36.8v.2h.1v-.2zM92.8 36.8l.2-.1 .1 .2v-.1l.3-.1v.1l-.3 .1v.1h.3v.1h-.6z"/>
<path d="M93 36l.3 .1v-.2zM92.8 35.8h.1v.3h.1v-.3h.2a.18 .18 0 0 1 .2 .2 .18 .18 0 0 1-.3 .2h-.2z"/>
<path d="M3.7 45v.2h.2zM3.6 45h.3l.1 .1-.2 .2h.1l.1 .2h-.1l-.1-.2h-.1v.2h-.1z"/>
<path d="M35.5 127.6v.2h.2v-.2zM35.4 127.6h.1h.2h.3l-.3 .1v.1h.3v.1h-.6z"/>
<path d="M82.4 137.5v.2l.2-.1v-.1zM82.3 137.4h.3v.1l-.1 .2 .1 .3-.1-.2h-.1v.2h-.1z"/>
<path d="M83.2 137.6v.2l.3-.3zM83.2 137.9l.3 .1v-.3zM83.2 137.4h.2a.34 .34 0 0 1 0 .6l-.3-.2z"/>
<path d="M87.3 137.5v.2l.2-.1v-.1zM87.2 137.4h.3v.1l-.1 .2 .1 .3-.1-.2h-.1v.2h-.1z"/>
<path d="M87.7 137.5v.2h.2v-.2zM87.6 137.5l.1-.1a.28 .28 0 0 1 .3 .2 .28 .28 0 0 1-.1 .4h-.3l.3-.1v-.1h-.3z"/>
<path d="M94.2 128.6v.1h.2v-.1zM94.1 128.6l.1-.1h.2v.1l.2-.1-.1 .2 .1 .1h-.5z"/>
<path d="M94.2 128.1v.2h.1l.1-.1zM94.5 128.1v.2h.1v-.2zM94.1 128.1l.2-.1 .1 .2 .1-.2h.1l.1 .2h-.1v.2h-.1l-.1-.2v.1h-.3z"/>
<path d="M94.2 123.9v.2h.2v-.2zM94.1 123.8h.3l.1 .1 .1-.1-.1 .1v.2h.1v.1h-.5z"/>
<path d="M94.4 123.4l.1 .3 .1-.1v-.2zM94.1 123.4l.3 .3a.22 .22 0 0 1 0-.3 .22 .22 0 0 1 .2-.1l.1 .3-.2 .1v.1l-.4-.2z"/>
<path d="M94.2 114.6v.2h.2v-.2zM94.1 114.6h.3h.1l.1-.1-.1 .1v.2h.1h-.5z"/>
<path d="M94.2 119.3v.2h.2v-.2zM94.1 119.2h.3l.1 .1v-.1l.2-.1v.1l-.2 .1v.2h.2h-.6z"/>
<path d="M86 33.6v.2h.2v-.3zM85.9 33.5h.4a.34 .34 0 0 1-.3 .5h-.1h.3v-.2v.1h-.2l-.1-.1z"/>
<path d="M80.8 33.7v.3l.2-.3zM80.6 33.6l.1-.1 .1 .1h.2l-.2 .4h-.1v-.3z"/>
<path d="M70.3 33.6v.3l.3-.2-.1-.2zM70.3 33.9l.2 .1h.1v-.3zM70.2 33.6a.24 .24 0 0 1 .3-.1 .24 .24 0 0 1 .1 .3v.1a.23 .23 0 0 1-.3 .1 .23 .23 0 0 1-.1-.3z"/>
<path d="M62.8 33.6v.2h.2v-.3zM62.7 33.5h.3a.34 .34 0 0 1-.2 .5h-.1h.3v-.2v.1h-.2l-.1-.1z"/>
<path d="M57.5 33.6v.1h.1v-.2zM57.5 33.9l.1 .1-.1-.2zM57.4 33.5h.3v.3h-.1h.1a.19 .19 0 0 1-.1 .2 .19 .19 0 0 1-.2 0l.1-.2z"/>
<path d="M85.7 12.1v.1a.55 .55 0 0 0 .2 .6l.4-.1 .1-.3a.45 .45 0 0 0-.2-.4 .45 .45 0 0 0-.5 .1zM84.8 11.8h.2v.5a.42 .42 0 0 0 .4 .4v.1h.2l-.1-.3a.56 .56 0 0 1 .1-.6 .56 .56 0 0 1 .6-.2l.2 .2a.55 .55 0 0 1 .2 .7 .55 .55 0 0 1-.6 .3v.1a1.19 1.19 0 0 1-1.2-.5z"/>
<path d="M60.1 12.8l.6 .7 .1-.1a.38 .38 0 0 0 .1-.5l-.2-.1zM59.5 13v.1a.46 .46 0 0 0 .6 .4h.3l-.6-.7zM59.3 12.8l.3-.1a.63 .63 0 0 1 .6-.2h.1a.73 .73 0 0 1 .9 .8 .86 .86 0 0 1-1.1 .5l-.5-.1-.1-.2a.43 .43 0 0 1-.2-.6z"/>
<path d="M35.1 12.3l.1 .2a.28 .28 0 0 0 .3 .2 .28 .28 0 0 0 .2-.4 .26 .26 0 0 0-.3-.2 .26 .26 0 0 0-.2 .2zM34.2 12.2a.38 .38 0 0 0 .2 .5v.1a.44 .44 0 0 0 .4-.4l.1-.1h-.1a.44 .44 0 0 0-.4-.3zM34.1 12v-.1a.34 .34 0 0 1 .6 0l.3 .3a.47 .47 0 0 1 .7-.4l.2 .5-.1 .2a.42 .42 0 0 1-.4 .5 .42 .42 0 0 1-.4-.4l-.1 .2-.2 .1a.47 .47 0 0 1-.6-.3z"/>
<path d="M64.8 49.5v1.9l1.3-1.9zM64.4 48.3h.4v.8h1.8v.4l-1.5 2.5h-.7v-2.5h-.7v-.4h.7z"/>
<path d="M109.6 143.3v.1a.24 .24 0 0 0-.1 .2 .24 .24 0 0 0 .2 .2l.2 .2h.1l.1-.2a.27 .27 0 0 0 .2-.3 .27 .27 0 0 0-.2-.2l-.2-.2zM109.3 143.2h.1a.55 .55 0 0 1 .6-.3 .55 .55 0 0 1 .4 .5h.1a1.09 1.09 0 0 1-.6 1l-.3 .1h-.3h-.2v-.1l-.4-.3 .1-.1 .2 .1a.63 .63 0 0 0 .7 .2l.2-.2-.1-.1a.59 .59 0 0 1-.5-.6z"/>
<path d="M18.4 119.6v.1a.33 .33 0 0 0 .1 .5 1.05 1.05 0 0 0 1.3-.1 .38 .38 0 0 0-.2-.5 .63 .63 0 0 0-.7-.1zM18.3 119.5l.1-.1a1.23 1.23 0 0 1 1.1-.1l.1 .1a.32 .32 0 0 1 .3 .4h.1a.3 .3 0 0 0 .3-.2 .3 .3 0 0 0-.1-.3l.2-.2v.3a.46 .46 0 0 1-.4 .6l-.1 .2a1.13 1.13 0 0 1-1.1 .4 .63 .63 0 0 1-.6-.9z"/>
</g>
</svg>
